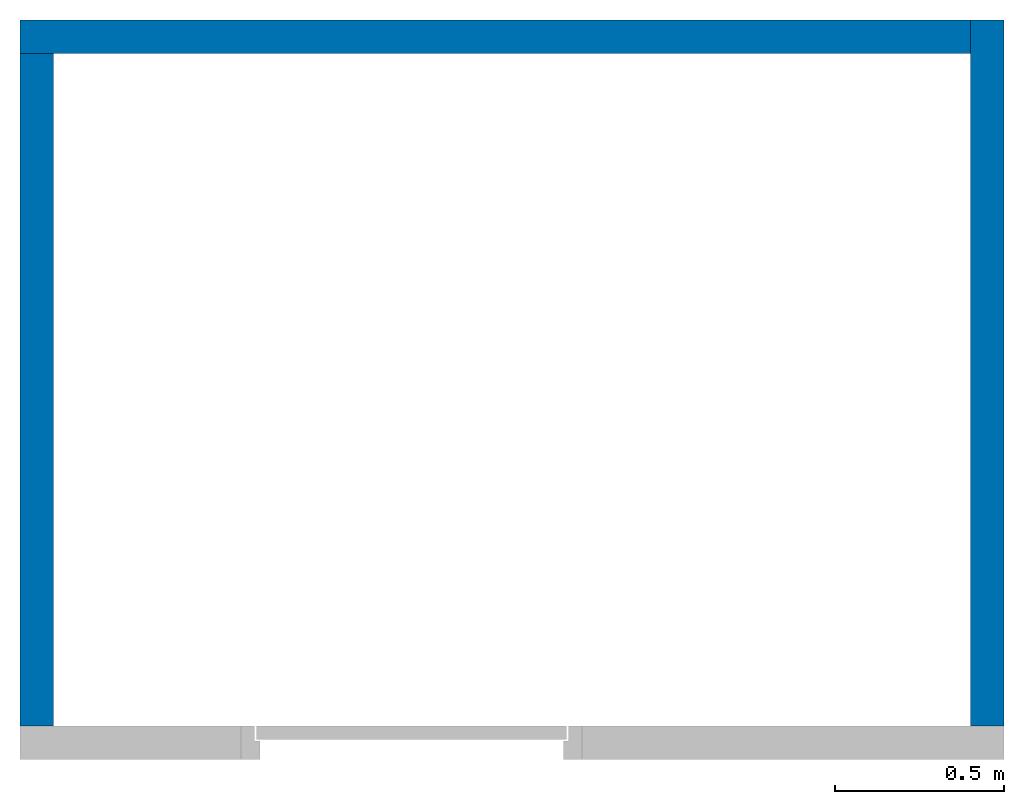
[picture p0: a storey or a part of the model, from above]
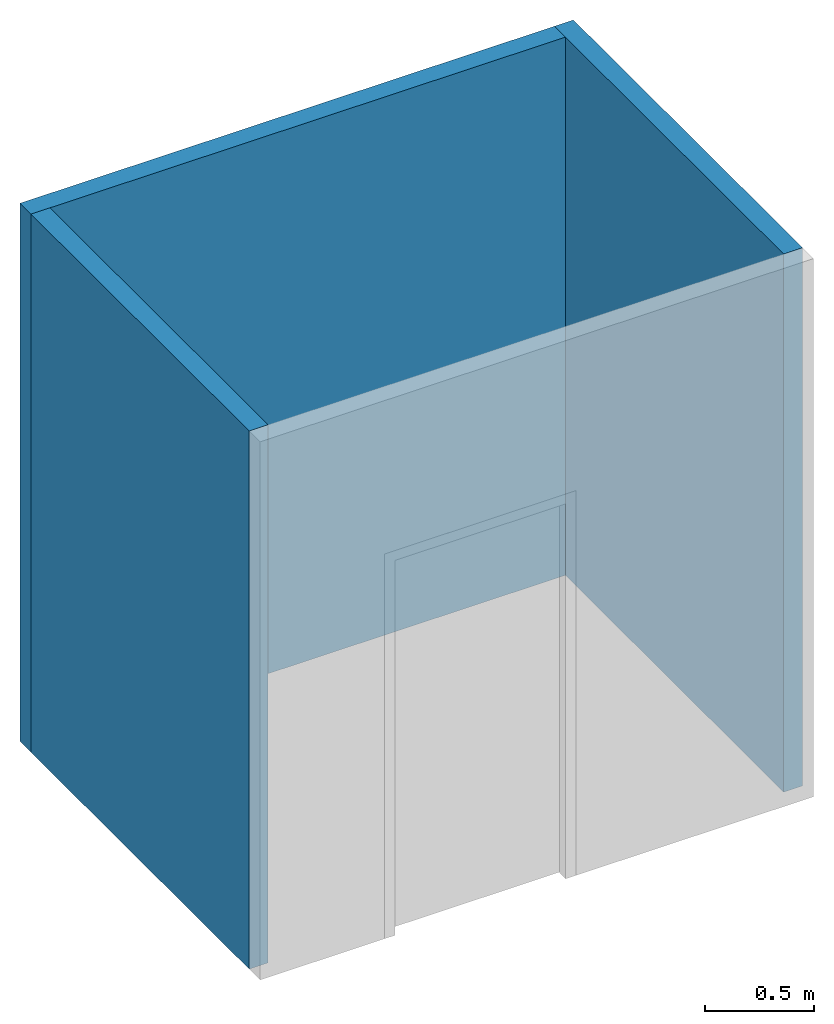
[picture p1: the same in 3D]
Properties of the parts of a building model (IFC4)

# File
Description: ViewDefinition[DesignTransferView]
File name: Smart tag_test.ifc
Time: 2024-07-05T10:05:42+08:00
Written by: IfcOpenShell v0.7.0-c7830e9e5
Made in: BlenderBIM 0.0.240602-47704b1
Authorization: Nobody

# IfcSpace, Garage
In: My Storey
Description: GARAGE; PredefinedType: INTERNAL

# IfcAnnotation: DIMENSION
Group: MY STOREY PLAN

# IfcAnnotation: DRAWING, MY STOREY PLAN
EPset_Drawing - TargetView: PLAN_VIEW; Scale: 1/50; HumanScale: 1:50; HasUnderlay: no; HasLinework: yes; HasAnnotation: yes; GlobalReferencing: yes
Group: MY STOREY PLAN

# IfcAnnotation: TEXT
Group: MY STOREY PLAN

# IfcDoor: DEMO1, Door
In: My Storey
EPset_Drawing - Scale: 1/100; HumanScale: 1:100

# IfcWall: DEMO100 (4)
In: My Storey
Type - Material: Unknown 100 mm
EPset_Parametric - Engine: BlenderBIM.DumbLayer2
Qto_WallBaseQuantities - Width: 100 mm; Height: 3000 mm
Name | Length (mm) | GrossFootprintArea (mm2) = NetFootprintArea (mm2) | GrossSideArea (mm2) | NetSideArea (mm2) | GrossVolume (mm3) | NetVolume (mm3)
Wall | 2917.94 | 0.29 | 8.75 | 6.59 | 0.88 | 0.66
Wall | 2093.2 | 0.21 | 6.28 | 6.28 | 0.63 | 0.63
Wall | 2817.95 | 0.28 | 8.45 | 8.45 | 0.85 | 0.85
Wall | 1993.2 | 0.2 | 5.98 | 5.98 | 0.6 | 0.6

# IfcBeamType, no part of this type: DEMO1
Material: Unknown

# IfcBeamType, no part of this type: DEMO2
Material: Unknown

# IfcColumnType, no part of this type: DEMO1
Material: Unknown

# IfcColumnType, no part of this type: DEMO2
Material: Unknown

# IfcColumnType, no part of this type: DEMO3
Material: Unknown

# IfcCoveringType, no part of this type: DEMO10
Material: Unknown 10 mm

# IfcCoveringType, no part of this type: DEMO20
Material: Unknown 20 mm
EPset_Parametric - LayerSetDirection: AXIS2

# IfcCoveringType, no part of this type: DEMO30
Material: Unknown 30 mm
EPset_Parametric - LayerSetDirection: AXIS3

# IfcPileType, no part of this type: DEMO1
Material: Unknown

# IfcRampType, no part of this type: DEMO200
Material: Unknown 200 mm

# IfcSlabType, no part of this type: DEMO150
Material: Unknown 200 mm

# IfcSlabType, no part of this type: DEMO250
Material: Unknown 300 mm

# IfcWallType, no part of this type: DEMO200
Material: Unknown 200 mm

# IfcWallType, no part of this type: DEMO300
Material: Unknown 300 mm

# IfcWallType, no part of this type: DEMO50
Material: Unknown 50 mm
